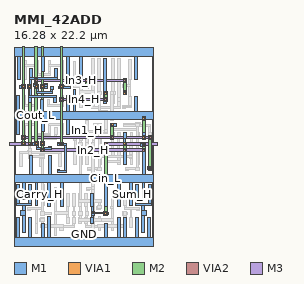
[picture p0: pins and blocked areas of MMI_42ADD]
MACRO MMI_42ADD
	CLASS CORE ;
	FOREIGN MMI_42ADD 0 0 ;
	SIZE 16.28 BY 22.2 ;
	SYMMETRY X Y ;
	SITE CORE1 ;
	PIN Sum_H
		DIRECTION output ;
		USE SIGNAL ;
		PORT
			LAYER M1 ;
			RECT 14.24 4.525 14.58 6.67 ;
			LAYER M1 ;
			RECT 15.68 4.525 16.02 6.67 ;
			LAYER M1 ;
			RECT 14.24 4.295 16.02 4.525 ;
			LAYER M1 ;
			RECT 14.91 3.64 15.25 4.295 ;
			LAYER M1 ;
			RECT 14.91 3.09 15.505 3.64 ;
			LAYER M1 ;
			RECT 14.91 1.1 15.25 3.09 ;
		END
		AntennaDiffArea 3.4977 ;
	END Sum_H
	PIN Carry_H
		DIRECTION output ;
		USE SIGNAL ;
		PORT
			LAYER M1 ;
			RECT 0.26 4.525 0.6 6.67 ;
			LAYER M1 ;
			RECT 1.7 4.525 2.04 6.67 ;
			LAYER M1 ;
			RECT 0.26 4.295 2.04 4.525 ;
			LAYER M1 ;
			RECT 1.03 3.64 1.37 4.295 ;
			LAYER M1 ;
			RECT 0.775 3.09 1.37 3.64 ;
			LAYER M1 ;
			RECT 1.03 1.1 1.37 3.09 ;
		END
		AntennaDiffArea 3.4977 ;
	END Carry_H
	PIN In2_H
		DIRECTION input ;
		USE SIGNAL ;
		PORT
			LAYER M1 ;
			RECT 3.59 18.355 3.93 18.51 ;
			LAYER M1 ;
			RECT 3.105 18.17 3.93 18.355 ;
			LAYER M1 ;
			RECT 3.105 17.905 3.92 18.17 ;
			LAYER M1 ;
			RECT 12.84 12.075 13.18 12.795 ;
			LAYER M1 ;
			RECT 3.105 11.245 3.555 11.695 ;
			LAYER M1 ;
			RECT 12.84 11.66 13.07 12.075 ;
			LAYER M1 ;
			RECT 12.76 11.28 13.14 11.66 ;
			LAYER M1 ;
			RECT 14.98 11.595 15.36 11.66 ;
			LAYER M1 ;
			RECT 14.97 11.545 15.375 11.595 ;
			LAYER M1 ;
			RECT 12.84 10.63 13.07 11.28 ;
			LAYER M1 ;
			RECT 14.81 11.205 15.375 11.545 ;
			LAYER M1 ;
			RECT 14.97 11.16 15.375 11.205 ;
			LAYER M1 ;
			RECT 12.84 9.11 13.18 10.63 ;
			LAYER VIA1 ;
			RECT 3.2 18 3.46 18.26 ;
			LAYER VIA1 ;
			RECT 3.2 11.34 3.46 11.6 ;
			LAYER VIA1 ;
			RECT 12.82 11.34 13.08 11.6 ;
			LAYER VIA1 ;
			RECT 15.04 11.34 15.3 11.6 ;
			LAYER M2 ;
			RECT 3.19 18.32 3.47 23.82 ;
			LAYER M2 ;
			RECT 3.14 17.94 3.52 18.32 ;
			LAYER M2 ;
			RECT 3.19 11.66 3.47 17.94 ;
			LAYER M2 ;
			RECT 3.14 11.28 3.52 11.66 ;
			LAYER M2 ;
			RECT 12.76 11.28 13.14 11.66 ;
			LAYER M2 ;
			RECT 14.98 11.28 15.36 11.66 ;
			LAYER M2 ;
			RECT 3.19 10.92 3.47 11.28 ;
			LAYER M2 ;
			RECT 12.81 10.92 13.09 11.28 ;
			LAYER M2 ;
			RECT 15.03 10.92 15.31 11.28 ;
			LAYER M2 ;
			RECT 3.14 10.54 3.52 10.92 ;
			LAYER M2 ;
			RECT 12.76 10.54 13.14 10.92 ;
			LAYER M2 ;
			RECT 14.98 10.54 15.36 10.92 ;
			LAYER VIA2 ;
			RECT 3.2 10.6 3.46 10.86 ;
			LAYER VIA2 ;
			RECT 12.82 10.6 13.08 10.86 ;
			LAYER VIA2 ;
			RECT 15.04 10.6 15.3 10.86 ;
			LAYER M3 ;
			RECT 3.14 10.87 3.52 10.92 ;
			LAYER M3 ;
			RECT 12.76 10.87 13.14 10.92 ;
			LAYER M3 ;
			RECT 14.98 10.87 15.36 10.92 ;
			LAYER M3 ;
			RECT 3.14 10.59 15.36 10.87 ;
			LAYER M3 ;
			RECT 3.14 10.54 3.52 10.59 ;
			LAYER M3 ;
			RECT 12.76 10.54 13.14 10.59 ;
			LAYER M3 ;
			RECT 14.98 10.54 15.36 10.59 ;
		END
		AntennaGateArea 2.7432 ;
		AntennaDiffArea 1.296 ;
	END In2_H
	PIN GND
		DIRECTION inout ;
		USE GROUND ;
		PORT
			LAYER M1 ;
			RECT 0.31 0.5 0.65 2.86 ;
			LAYER M1 ;
			RECT 1.75 0.5 2.09 2.86 ;
			LAYER M1 ;
			RECT 3.18 0.5 3.52 2.12 ;
			LAYER M1 ;
			RECT 3.96 0.5 4.3 2.925 ;
			LAYER M1 ;
			RECT 10.62 0.5 10.96 2.165 ;
			LAYER M1 ;
			RECT 12.06 0.5 12.4 2.875 ;
			LAYER M1 ;
			RECT 12.76 0.5 13.1 2.86 ;
			LAYER M1 ;
			RECT 14.19 0.5 14.53 2.86 ;
			LAYER M1 ;
			RECT 15.63 0.5 15.97 2.86 ;
			LAYER M1 ;
			RECT 0 -0.5 16.28 0.5 ;
			LAYER M1 ;
			RECT 0.26 15.3 0.6 17.13 ;
			LAYER M1 ;
			RECT 3.14 15.3 3.48 16.64 ;
			LAYER M1 ;
			RECT 6.14 15.3 6.48 17.13 ;
			LAYER M1 ;
			RECT 6.9 15.3 7.24 17.795 ;
			LAYER M1 ;
			RECT 14.08 15.3 14.42 16.965 ;
			LAYER M1 ;
			RECT 0 14.3 16.28 15.3 ;
			LAYER M1 ;
			RECT 0.3 12.555 0.64 14.3 ;
			LAYER M1 ;
			RECT 3.22 12.955 3.56 14.3 ;
			LAYER M1 ;
			RECT 6.14 12.555 6.48 14.3 ;
			LAYER M1 ;
			RECT 14.98 14.24 15.36 14.3 ;
			LAYER M1 ;
			RECT 15 12.4 15.34 12.795 ;
			LAYER M1 ;
			RECT 14.98 12.02 15.36 12.4 ;
			LAYER VIA1 ;
			RECT 15.04 14.3 15.3 14.56 ;
			LAYER VIA1 ;
			RECT 15.04 12.08 15.3 12.34 ;
			LAYER M2 ;
			RECT 14.98 14.24 15.36 14.62 ;
			LAYER M2 ;
			RECT 15.03 12.4 15.31 14.24 ;
			LAYER M2 ;
			RECT 14.98 12.02 15.36 12.4 ;
		END
	END GND
	PIN Cin_L
		DIRECTION input ;
		USE SIGNAL ;
		PORT
			LAYER M1 ;
			RECT 8.98 4.17 9.32 5.69 ;
			LAYER M1 ;
			RECT 9.09 3.52 9.32 4.17 ;
			LAYER M1 ;
			RECT 9.06 3.505 9.44 3.52 ;
			LAYER M1 ;
			RECT 10.505 3.505 10.955 3.555 ;
			LAYER M1 ;
			RECT 9.06 3.495 10.955 3.505 ;
			LAYER M1 ;
			RECT 9.06 3.275 11.09 3.495 ;
			LAYER M1 ;
			RECT 9.06 3.14 9.44 3.275 ;
			LAYER M1 ;
			RECT 10.505 3.155 11.09 3.275 ;
			LAYER M1 ;
			RECT 9.09 2.91 9.32 3.14 ;
			LAYER M1 ;
			RECT 10.505 3.105 10.955 3.155 ;
			LAYER M1 ;
			RECT 8.98 2.19 9.32 2.91 ;
			LAYER VIA1 ;
			RECT 10.6 3.2 10.86 3.46 ;
			LAYER M2 ;
			RECT 10.54 11.28 10.92 11.66 ;
			LAYER M2 ;
			RECT 10.59 3.52 10.87 11.28 ;
			LAYER M2 ;
			RECT 10.54 3.14 10.92 3.52 ;
			LAYER VIA2 ;
			RECT 10.6 11.34 10.86 11.6 ;
			LAYER M3 ;
			RECT 10.54 11.61 10.92 11.66 ;
			LAYER M3 ;
			RECT 10.54 11.33 16.79 11.61 ;
			LAYER M3 ;
			RECT 10.54 11.28 10.92 11.33 ;
		END
		AntennaGateArea 1.152 ;
		AntennaDiffArea 1.152 ;
	END Cin_L
	PIN In3_H
		DIRECTION input ;
		USE SIGNAL ;
		PORT
			LAYER M1 ;
			RECT 2.305 18.355 2.645 18.505 ;
			LAYER M1 ;
			RECT 2.305 18.165 2.815 18.355 ;
			LAYER M1 ;
			RECT 8.415 18.34 8.755 18.41 ;
			LAYER M1 ;
			RECT 2.365 17.905 2.815 18.165 ;
			LAYER M1 ;
			RECT 2.585 17.615 2.815 17.905 ;
			LAYER M1 ;
			RECT 4.32 17.795 4.66 18.135 ;
			LAYER M1 ;
			RECT 8.32 17.895 8.755 18.34 ;
			LAYER M1 ;
			RECT 4.32 17.615 4.55 17.795 ;
			LAYER M1 ;
			RECT 2.585 17.385 4.55 17.615 ;
			LAYER M1 ;
			RECT 12.76 17.2 13.14 17.755 ;
			LAYER M1 ;
			RECT 2.365 11.64 2.815 11.695 ;
			LAYER M1 ;
			RECT 2.16 11.585 2.815 11.64 ;
			LAYER M1 ;
			RECT 2.16 11.3 2.855 11.585 ;
			LAYER M1 ;
			RECT 2.365 11.245 2.855 11.3 ;
			LAYER M1 ;
			RECT 2.625 11.015 2.855 11.245 ;
			LAYER M1 ;
			RECT 4.01 11.015 4.35 11.2 ;
			LAYER M1 ;
			RECT 2.625 10.86 4.35 11.015 ;
			LAYER M1 ;
			RECT 2.625 10.785 4.245 10.86 ;
			LAYER VIA1 ;
			RECT 2.46 18 2.72 18.26 ;
			LAYER VIA1 ;
			RECT 8.38 18 8.64 18.26 ;
			LAYER VIA1 ;
			RECT 12.82 17.26 13.08 17.52 ;
			LAYER VIA1 ;
			RECT 2.46 11.34 2.72 11.6 ;
			LAYER M2 ;
			RECT 2.45 19.06 2.73 23.82 ;
			LAYER M2 ;
			RECT 2.4 18.68 2.78 19.06 ;
			LAYER M2 ;
			RECT 8.32 18.68 8.7 19.06 ;
			LAYER M2 ;
			RECT 12.76 18.68 13.14 19.06 ;
			LAYER M2 ;
			RECT 2.45 18.32 2.73 18.68 ;
			LAYER M2 ;
			RECT 8.37 18.32 8.65 18.68 ;
			LAYER M2 ;
			RECT 2.4 17.94 2.78 18.32 ;
			LAYER M2 ;
			RECT 8.32 17.94 8.7 18.32 ;
			LAYER M2 ;
			RECT 2.45 11.66 2.73 17.94 ;
			LAYER M2 ;
			RECT 12.81 17.58 13.09 18.68 ;
			LAYER M2 ;
			RECT 12.76 17.2 13.14 17.58 ;
			LAYER M2 ;
			RECT 2.4 11.28 2.78 11.66 ;
			LAYER VIA2 ;
			RECT 2.46 18.74 2.72 19 ;
			LAYER VIA2 ;
			RECT 8.38 18.74 8.64 19 ;
			LAYER VIA2 ;
			RECT 12.82 18.74 13.08 19 ;
			LAYER M3 ;
			RECT 2.4 19.01 2.78 19.06 ;
			LAYER M3 ;
			RECT 8.32 19.01 8.7 19.06 ;
			LAYER M3 ;
			RECT 12.76 19.01 13.14 19.06 ;
			LAYER M3 ;
			RECT 2.4 18.73 13.14 19.01 ;
			LAYER M3 ;
			RECT 2.4 18.68 2.78 18.73 ;
			LAYER M3 ;
			RECT 8.32 18.68 8.7 18.73 ;
			LAYER M3 ;
			RECT 12.76 18.68 13.14 18.73 ;
		END
		AntennaGateArea 4.6872 ;
	END In3_H
	PIN VDD
		DIRECTION inout ;
		USE POWER ;
		PORT
			LAYER M1 ;
			RECT 1.78 7.9 2.12 10.055 ;
			LAYER M1 ;
			RECT 4.08 7.9 4.42 10.055 ;
			LAYER M1 ;
			RECT 15 7.9 15.34 10.63 ;
			LAYER M1 ;
			RECT 0 6.9 16.28 7.9 ;
			LAYER M1 ;
			RECT 0.98 4.915 1.32 6.9 ;
			LAYER M1 ;
			RECT 2.46 4.27 2.8 6.9 ;
			LAYER M1 ;
			RECT 3.96 4.19 4.3 6.9 ;
			LAYER M1 ;
			RECT 5.4 4.19 5.74 6.9 ;
			LAYER M1 ;
			RECT 10.62 4.19 10.96 6.9 ;
			LAYER M1 ;
			RECT 12.06 4.19 12.4 6.9 ;
			LAYER M1 ;
			RECT 13.48 4.27 13.82 6.9 ;
			LAYER M1 ;
			RECT 14.96 4.915 15.3 6.9 ;
			LAYER M1 ;
			RECT 0 21.7 16.28 22.7 ;
			LAYER M1 ;
			RECT 0.38 18.97 0.72 21.7 ;
			LAYER M1 ;
			RECT 3.26 19.89 3.6 21.7 ;
			LAYER M1 ;
			RECT 6.14 18.97 6.48 21.7 ;
			LAYER M1 ;
			RECT 7.62 18.97 7.96 21.7 ;
			LAYER M1 ;
			RECT 14.08 18.97 14.42 21.7 ;
		END
	END VDD
	PIN Cout_L
		DIRECTION output ;
		USE SIGNAL ;
		PORT
			LAYER M1 ;
			RECT 1.82 19.2 2.16 20.25 ;
			LAYER M1 ;
			RECT 4.7 19.2 5.04 20.25 ;
			LAYER M1 ;
			RECT 1.82 18.97 5.04 19.2 ;
			LAYER M1 ;
			RECT 1.82 18.355 2.05 18.97 ;
			LAYER M1 ;
			RECT 1.625 17.905 2.075 18.355 ;
			LAYER M1 ;
			RECT 1.775 17.13 2.005 17.905 ;
			LAYER M1 ;
			RECT 1.7 17.1 2.04 17.13 ;
			LAYER M1 ;
			RECT 4.58 17.1 4.92 17.13 ;
			LAYER M1 ;
			RECT 1.7 16.87 4.925 17.1 ;
			LAYER M1 ;
			RECT 1.7 16.32 2.04 16.87 ;
			LAYER M1 ;
			RECT 4.58 16.32 4.92 16.87 ;
			LAYER VIA1 ;
			RECT 1.72 18 1.98 18.26 ;
			LAYER M2 ;
			RECT 1.66 17.94 2.04 18.32 ;
			LAYER M2 ;
			RECT 1.71 11.66 1.99 17.94 ;
			LAYER M2 ;
			RECT 1.66 11.28 2.04 11.66 ;
			LAYER VIA2 ;
			RECT 1.72 11.34 1.98 11.6 ;
			LAYER M3 ;
			RECT 1.66 11.61 2.04 11.66 ;
			LAYER M3 ;
			RECT -0.51 11.33 2.04 11.61 ;
			LAYER M3 ;
			RECT 1.66 11.28 2.04 11.33 ;
		END
		AntennaDiffArea 3.9528 ;
	END Cout_L
	PIN In4_H
		DIRECTION input ;
		USE SIGNAL ;
		PORT
			LAYER M1 ;
			RECT 5.325 18.355 5.57 18.36 ;
			LAYER M1 ;
			RECT 5.325 18.3 5.775 18.355 ;
			LAYER M1 ;
			RECT 5.325 18.225 6.635 18.3 ;
			LAYER M1 ;
			RECT 5.22 17.96 6.635 18.225 ;
			LAYER M1 ;
			RECT 5.22 17.905 5.775 17.96 ;
			LAYER M1 ;
			RECT 5.22 17.885 5.56 17.905 ;
			LAYER M1 ;
			RECT 5.325 17.88 5.56 17.885 ;
			LAYER M1 ;
			RECT 10.495 17.58 10.835 21.47 ;
			LAYER M1 ;
			RECT 10.495 17.2 10.92 17.58 ;
			LAYER M1 ;
			RECT 10.495 16.16 10.835 17.2 ;
			LAYER M1 ;
			RECT 5.36 11.645 5.74 11.66 ;
			LAYER M1 ;
			RECT 5.07 11.525 5.74 11.645 ;
			LAYER M1 ;
			RECT 5.07 11.51 5.775 11.525 ;
			LAYER M1 ;
			RECT 5.07 11.305 6.11 11.51 ;
			LAYER M1 ;
			RECT 5.36 11.28 6.11 11.305 ;
			LAYER M1 ;
			RECT 5.03 8.405 5.37 8.51 ;
			LAYER M1 ;
			RECT 5.88 8.405 6.11 11.28 ;
			LAYER M1 ;
			RECT 5.03 8.175 6.11 8.405 ;
			LAYER M1 ;
			RECT 5.03 8.17 5.37 8.175 ;
			LAYER VIA1 ;
			RECT 5.42 18 5.68 18.26 ;
			LAYER VIA1 ;
			RECT 10.6 17.26 10.86 17.52 ;
			LAYER VIA1 ;
			RECT 5.42 11.34 5.68 11.6 ;
			LAYER M2 ;
			RECT 5.41 18.32 5.69 23.82 ;
			LAYER M2 ;
			RECT 5.36 17.94 5.74 18.32 ;
			LAYER M2 ;
			RECT 5.41 16.84 5.69 17.94 ;
			LAYER M2 ;
			RECT 10.54 17.2 10.92 17.58 ;
			LAYER M2 ;
			RECT 10.59 16.84 10.87 17.2 ;
			LAYER M2 ;
			RECT 5.36 16.46 5.74 16.84 ;
			LAYER M2 ;
			RECT 10.54 16.46 10.92 16.84 ;
			LAYER M2 ;
			RECT 5.41 11.66 5.69 16.46 ;
			LAYER M2 ;
			RECT 5.36 11.28 5.74 11.66 ;
			LAYER VIA2 ;
			RECT 5.42 16.52 5.68 16.78 ;
			LAYER VIA2 ;
			RECT 10.6 16.52 10.86 16.78 ;
			LAYER M3 ;
			RECT 5.36 16.79 5.74 16.84 ;
			LAYER M3 ;
			RECT 10.54 16.79 10.92 16.84 ;
			LAYER M3 ;
			RECT 5.36 16.51 10.92 16.79 ;
			LAYER M3 ;
			RECT 5.36 16.46 5.74 16.51 ;
			LAYER M3 ;
			RECT 10.54 16.46 10.92 16.51 ;
		END
		AntennaGateArea 3.4992 ;
		AntennaDiffArea 3.312 ;
	END In4_H
	PIN In1_H
		DIRECTION input ;
		USE SIGNAL ;
		PORT
			LAYER M1 ;
			RECT 0.885 18.3 1.335 18.355 ;
			LAYER M1 ;
			RECT 0.7 17.96 1.335 18.3 ;
			LAYER M1 ;
			RECT 0.885 17.905 1.335 17.96 ;
			LAYER M1 ;
			RECT 11.28 13.855 11.66 13.88 ;
			LAYER M1 ;
			RECT 11.28 13.515 11.98 13.855 ;
			LAYER M1 ;
			RECT 11.28 13.5 11.66 13.515 ;
			LAYER M1 ;
			RECT 0.885 11.245 1.335 11.695 ;
			LAYER M1 ;
			RECT 15.57 8.7 15.91 8.765 ;
			LAYER M1 ;
			RECT 15.57 8.425 16.1 8.7 ;
			LAYER M1 ;
			RECT 15.72 8.32 16.1 8.425 ;
			LAYER VIA1 ;
			RECT 0.98 18 1.24 18.26 ;
			LAYER VIA1 ;
			RECT 11.34 13.56 11.6 13.82 ;
			LAYER VIA1 ;
			RECT 0.98 11.34 1.24 11.6 ;
			LAYER VIA1 ;
			RECT 15.78 8.38 16.04 8.64 ;
			LAYER M2 ;
			RECT 0.97 18.32 1.25 23.82 ;
			LAYER M2 ;
			RECT 0.92 17.94 1.3 18.32 ;
			LAYER M2 ;
			RECT 0.97 12.4 1.25 17.94 ;
			LAYER M2 ;
			RECT 11.28 13.5 11.66 13.88 ;
			LAYER M2 ;
			RECT 11.33 12.4 11.61 13.5 ;
			LAYER M2 ;
			RECT 0.92 12.02 1.3 12.4 ;
			LAYER M2 ;
			RECT 11.28 12.02 11.66 12.4 ;
			LAYER M2 ;
			RECT 15.72 12.02 16.1 12.4 ;
			LAYER M2 ;
			RECT 0.97 11.66 1.25 12.02 ;
			LAYER M2 ;
			RECT 0.92 11.28 1.3 11.66 ;
			LAYER M2 ;
			RECT 15.77 8.7 16.05 12.02 ;
			LAYER M2 ;
			RECT 15.72 8.32 16.1 8.7 ;
			LAYER VIA2 ;
			RECT 0.98 12.08 1.24 12.34 ;
			LAYER VIA2 ;
			RECT 11.34 12.08 11.6 12.34 ;
			LAYER VIA2 ;
			RECT 15.78 12.08 16.04 12.34 ;
			LAYER M3 ;
			RECT 0.92 12.35 1.3 12.4 ;
			LAYER M3 ;
			RECT 11.28 12.35 11.66 12.4 ;
			LAYER M3 ;
			RECT 15.72 12.35 16.1 12.4 ;
			LAYER M3 ;
			RECT 0.92 12.07 16.1 12.35 ;
			LAYER M3 ;
			RECT 0.92 12.02 1.3 12.07 ;
			LAYER M3 ;
			RECT 11.28 12.02 11.66 12.07 ;
			LAYER M3 ;
			RECT 15.72 12.02 16.1 12.07 ;
		END
		AntennaGateArea 3.6072 ;
	END In1_H
	OBS
		LAYER M1 ;
		RECT 1.1 20.72 1.44 21.17 ;
		LAYER M1 ;
		RECT 2.54 20.72 2.88 21.17 ;
		LAYER M1 ;
		RECT 1.1 20.49 2.88 20.72 ;
		LAYER M1 ;
		RECT 1.1 18.97 1.44 20.49 ;
		LAYER M1 ;
		RECT 2.54 19.89 2.88 20.49 ;
		LAYER M1 ;
		RECT 3.98 20.715 4.32 21.17 ;
		LAYER M1 ;
		RECT 5.42 20.715 5.76 21.17 ;
		LAYER M1 ;
		RECT 3.98 20.485 5.76 20.715 ;
		LAYER M1 ;
		RECT 3.98 19.89 4.32 20.485 ;
		LAYER M1 ;
		RECT 2.59 19.66 2.82 19.89 ;
		LAYER M1 ;
		RECT 4.03 19.66 4.26 19.89 ;
		LAYER M1 ;
		RECT 2.59 19.43 4.26 19.66 ;
		LAYER M1 ;
		RECT 5.42 18.97 5.76 20.485 ;
		LAYER M1 ;
		RECT 6.9 18.43 7.24 21.09 ;
		LAYER M1 ;
		RECT 6.9 18.035 7.96 18.43 ;
		LAYER M1 ;
		RECT 0.98 16.08 1.32 17.13 ;
		LAYER M1 ;
		RECT 2.42 16.08 2.76 16.64 ;
		LAYER M1 ;
		RECT 0.98 15.85 2.76 16.08 ;
		LAYER M1 ;
		RECT 0.98 15.83 1.32 15.85 ;
		LAYER M1 ;
		RECT 2.42 15.83 2.76 15.85 ;
		LAYER M1 ;
		RECT 3.86 16.07 4.2 16.64 ;
		LAYER M1 ;
		RECT 5.42 16.07 5.76 17.13 ;
		LAYER M1 ;
		RECT 3.86 15.84 5.76 16.07 ;
		LAYER M1 ;
		RECT 3.86 15.83 4.2 15.84 ;
		LAYER M1 ;
		RECT 5.42 15.83 5.76 15.84 ;
		LAYER M1 ;
		RECT 7.62 17.665 7.96 18.035 ;
		LAYER M1 ;
		RECT 9.055 17.665 9.395 21.47 ;
		LAYER M1 ;
		RECT 7.62 17.385 9.395 17.665 ;
		LAYER M1 ;
		RECT 7.62 15.675 7.96 17.385 ;
		LAYER M1 ;
		RECT 9.055 16.885 9.395 17.385 ;
		LAYER M1 ;
		RECT 9.05 15.89 9.395 16.885 ;
		LAYER M1 ;
		RECT 9.775 17.58 10.115 21.47 ;
		LAYER M1 ;
		RECT 11.365 17.58 11.705 21.47 ;
		LAYER M1 ;
		RECT 9.775 17.2 10.18 17.58 ;
		LAYER M1 ;
		RECT 11.28 17.2 11.81 17.58 ;
		LAYER M1 ;
		RECT 9.775 16.16 10.115 17.2 ;
		LAYER M1 ;
		RECT 11.365 16.16 11.705 17.2 ;
		LAYER M1 ;
		RECT 12.085 16.88 12.425 21.47 ;
		LAYER M1 ;
		RECT 13.36 18.97 13.7 21.29 ;
		LAYER M1 ;
		RECT 12.665 18.36 13.005 18.41 ;
		LAYER M1 ;
		RECT 13.42 18.36 13.65 18.97 ;
		LAYER M1 ;
		RECT 12.665 18.13 13.65 18.36 ;
		LAYER M1 ;
		RECT 12.665 18.07 13.005 18.13 ;
		LAYER M1 ;
		RECT 13.42 16.965 13.65 18.13 ;
		LAYER M1 ;
		RECT 12.085 16.36 12.49 16.88 ;
		LAYER M1 ;
		RECT 12.15 15.89 12.49 16.36 ;
		LAYER M1 ;
		RECT 13.36 15.95 13.7 16.965 ;
		LAYER M1 ;
		RECT 9.05 15.605 12.49 15.89 ;
		LAYER M1 ;
		RECT 12.72 15.845 13.7 15.95 ;
		LAYER M1 ;
		RECT 12.72 15.72 13.695 15.845 ;
		LAYER M1 ;
		RECT 12.72 15.61 13.06 15.72 ;
		LAYER M1 ;
		RECT 9.055 15.6 12.49 15.605 ;
		LAYER M1 ;
		RECT 9.055 15.59 12.37 15.6 ;
		LAYER M1 ;
		RECT 1.02 13.625 2.8 13.855 ;
		LAYER M1 ;
		RECT 1.02 12.555 1.36 13.625 ;
		LAYER M1 ;
		RECT 1.74 12.555 2.08 13.395 ;
		LAYER M1 ;
		RECT 2.46 12.625 2.8 13.625 ;
		LAYER M1 ;
		RECT 3.98 13.625 5.76 13.855 ;
		LAYER M1 ;
		RECT 3.98 12.625 4.32 13.625 ;
		LAYER M1 ;
		RECT 2.46 12.555 4.32 12.625 ;
		LAYER M1 ;
		RECT 4.7 12.555 5.04 13.395 ;
		LAYER M1 ;
		RECT 5.42 12.555 5.76 13.625 ;
		LAYER M1 ;
		RECT 9.675 13.795 10.18 13.88 ;
		LAYER M1 ;
		RECT 9.34 13.5 10.18 13.795 ;
		LAYER M1 ;
		RECT 14.18 13.85 14.75 13.91 ;
		LAYER M1 ;
		RECT 12.75 13.77 14.75 13.85 ;
		LAYER M1 ;
		RECT 12.75 13.54 16 13.77 ;
		LAYER M1 ;
		RECT 12.75 13.51 14.75 13.54 ;
		LAYER M1 ;
		RECT 14.18 13.5 14.75 13.51 ;
		LAYER M1 ;
		RECT 9.34 13.455 9.68 13.5 ;
		LAYER M1 ;
		RECT 10.54 13.075 10.92 13.14 ;
		LAYER M1 ;
		RECT 7.005 12.845 10.92 13.075 ;
		LAYER M1 ;
		RECT 7.005 12.615 7.235 12.845 ;
		LAYER M1 ;
		RECT 9.95 12.76 10.92 12.845 ;
		LAYER M1 ;
		RECT 11.445 13.025 14.57 13.255 ;
		LAYER M1 ;
		RECT 11.445 12.795 11.675 13.025 ;
		LAYER M1 ;
		RECT 14.34 12.795 14.57 13.025 ;
		LAYER M1 ;
		RECT 15.77 12.795 16 13.54 ;
		LAYER M1 ;
		RECT 9.95 12.695 10.875 12.76 ;
		LAYER M1 ;
		RECT 9.95 12.615 10.18 12.695 ;
		LAYER M1 ;
		RECT 1.85 12.155 2.08 12.555 ;
		LAYER M1 ;
		RECT 2.57 12.395 4.21 12.555 ;
		LAYER M1 ;
		RECT 4.7 12.155 4.93 12.555 ;
		LAYER M1 ;
		RECT 1.7 11.925 4.93 12.155 ;
		LAYER M1 ;
		RECT 1.7 10.92 1.93 11.925 ;
		LAYER M1 ;
		RECT 6.96 11.895 7.3 12.615 ;
		LAYER M1 ;
		RECT 7.68 11.895 8.02 12.615 ;
		LAYER M1 ;
		RECT 8.4 11.895 8.74 12.615 ;
		LAYER M1 ;
		RECT 9.12 11.895 9.46 12.615 ;
		LAYER M1 ;
		RECT 9.84 11.895 10.18 12.615 ;
		LAYER M1 ;
		RECT 1.66 10.72 2.04 10.92 ;
		LAYER M1 ;
		RECT 1.53 10.545 2.04 10.72 ;
		LAYER M1 ;
		RECT 0.63 10.315 5.57 10.545 ;
		LAYER M1 ;
		RECT 0.63 8.775 0.97 10.315 ;
		LAYER M1 ;
		RECT 2.93 8.775 3.27 10.315 ;
		LAYER M1 ;
		RECT 5.23 8.775 5.57 10.315 ;
		LAYER M1 ;
		RECT 7.015 10.63 7.245 11.895 ;
		LAYER M1 ;
		RECT 7.685 11.66 7.915 11.895 ;
		LAYER M1 ;
		RECT 8.4 11.66 8.63 11.895 ;
		LAYER M1 ;
		RECT 9.155 11.66 9.385 11.895 ;
		LAYER M1 ;
		RECT 7.58 11.28 7.96 11.66 ;
		LAYER M1 ;
		RECT 8.32 11.28 8.7 11.66 ;
		LAYER M1 ;
		RECT 9.06 11.28 9.44 11.66 ;
		LAYER M1 ;
		RECT 7.685 10.63 7.915 11.28 ;
		LAYER M1 ;
		RECT 8.4 10.63 8.63 11.28 ;
		LAYER M1 ;
		RECT 9.155 10.63 9.385 11.28 ;
		LAYER M1 ;
		RECT 9.95 10.63 10.18 11.895 ;
		LAYER M1 ;
		RECT 11.4 12.075 11.74 12.795 ;
		LAYER M1 ;
		RECT 12.12 12.075 12.46 12.795 ;
		LAYER M1 ;
		RECT 13.56 12.075 13.9 12.795 ;
		LAYER M1 ;
		RECT 14.28 12.075 14.62 12.795 ;
		LAYER M1 ;
		RECT 10.54 11.265 10.92 11.29 ;
		LAYER M1 ;
		RECT 10.415 10.925 10.92 11.265 ;
		LAYER M1 ;
		RECT 10.54 10.91 10.92 10.925 ;
		LAYER M1 ;
		RECT 6.96 9.11 7.3 10.63 ;
		LAYER M1 ;
		RECT 7.68 9.11 8.02 10.63 ;
		LAYER M1 ;
		RECT 8.4 9.11 8.74 10.63 ;
		LAYER M1 ;
		RECT 9.12 9.11 9.46 10.63 ;
		LAYER M1 ;
		RECT 9.84 9.11 10.18 10.63 ;
		LAYER M1 ;
		RECT 10.615 9.575 10.845 10.91 ;
		LAYER M1 ;
		RECT 11.4 10.63 11.63 12.075 ;
		LAYER M1 ;
		RECT 12.125 11.66 12.355 12.075 ;
		LAYER M1 ;
		RECT 13.595 11.66 13.825 12.075 ;
		LAYER M1 ;
		RECT 12.02 11.28 12.4 11.66 ;
		LAYER M1 ;
		RECT 13.5 11.28 13.88 11.66 ;
		LAYER M1 ;
		RECT 12.125 10.63 12.355 11.28 ;
		LAYER M1 ;
		RECT 13.595 10.63 13.825 11.28 ;
		LAYER M1 ;
		RECT 14.35 10.63 14.58 12.075 ;
		LAYER M1 ;
		RECT 15.72 12.075 16.06 12.795 ;
		LAYER M1 ;
		RECT 15.83 10.63 16.06 12.075 ;
		LAYER M1 ;
		RECT 11.4 9.82 11.74 10.63 ;
		LAYER M1 ;
		RECT 12.12 9.575 12.46 10.63 ;
		LAYER M1 ;
		RECT 10.615 9.345 12.46 9.575 ;
		LAYER M1 ;
		RECT 12.12 9.11 12.46 9.345 ;
		LAYER M1 ;
		RECT 13.56 9.11 13.9 10.63 ;
		LAYER M1 ;
		RECT 14.28 9.11 14.62 10.63 ;
		LAYER M1 ;
		RECT 8.64 8.675 8.98 8.725 ;
		LAYER M1 ;
		RECT 9.675 8.675 10.18 8.7 ;
		LAYER M1 ;
		RECT 8.64 8.445 10.18 8.675 ;
		LAYER M1 ;
		RECT 8.64 8.385 8.98 8.445 ;
		LAYER M1 ;
		RECT 9.675 8.32 10.18 8.445 ;
		LAYER M1 ;
		RECT 13.08 8.675 13.42 8.725 ;
		LAYER M1 ;
		RECT 14.24 8.675 14.62 8.7 ;
		LAYER M1 ;
		RECT 13.08 8.445 14.64 8.675 ;
		LAYER M1 ;
		RECT 13.08 8.385 13.42 8.445 ;
		LAYER M1 ;
		RECT 14.24 8.32 14.62 8.445 ;
		LAYER M1 ;
		RECT 15.72 9.11 16.06 10.63 ;
		LAYER M1 ;
		RECT 3.18 4.27 3.52 6.67 ;
		LAYER M1 ;
		RECT 1.61 4.02 1.95 4.025 ;
		LAYER M1 ;
		RECT 3.265 4.02 3.495 4.27 ;
		LAYER M1 ;
		RECT 1.61 3.79 3.495 4.02 ;
		LAYER M1 ;
		RECT 1.61 3.685 1.95 3.79 ;
		LAYER M1 ;
		RECT 2.46 2.12 2.69 3.79 ;
		LAYER M1 ;
		RECT 4.68 3.57 5.02 6.31 ;
		LAYER M1 ;
		RECT 8.46 6.405 8.8 6.415 ;
		LAYER M1 ;
		RECT 9.06 6.405 9.44 6.48 ;
		LAYER M1 ;
		RECT 8.46 6.175 9.44 6.405 ;
		LAYER M1 ;
		RECT 8.46 6.075 8.8 6.175 ;
		LAYER M1 ;
		RECT 9.06 6.1 9.44 6.175 ;
		LAYER M1 ;
		RECT 6.1 4.17 6.44 5.69 ;
		LAYER M1 ;
		RECT 6.82 4.17 7.16 5.69 ;
		LAYER M1 ;
		RECT 7.54 4.17 7.88 5.69 ;
		LAYER M1 ;
		RECT 8.26 4.17 8.6 5.69 ;
		LAYER M1 ;
		RECT 6.1 3.57 6.33 4.17 ;
		LAYER M1 ;
		RECT 3.105 3.445 3.555 3.555 ;
		LAYER M1 ;
		RECT 4.02 3.445 4.36 3.5 ;
		LAYER M1 ;
		RECT 3.105 3.215 4.36 3.445 ;
		LAYER M1 ;
		RECT 3.105 3.105 3.555 3.215 ;
		LAYER M1 ;
		RECT 4.02 3.16 4.36 3.215 ;
		LAYER M1 ;
		RECT 4.68 3.23 6.33 3.57 ;
		LAYER M1 ;
		RECT 6.895 3.52 7.125 4.17 ;
		LAYER M1 ;
		RECT 7.65 3.52 7.88 4.17 ;
		LAYER M1 ;
		RECT 8.365 3.52 8.595 4.17 ;
		LAYER M1 ;
		RECT 9.8 4.09 10.18 4.26 ;
		LAYER M1 ;
		RECT 11.34 4.185 11.68 5.71 ;
		LAYER M1 ;
		RECT 12.76 4.27 13.1 6.05 ;
		LAYER M1 ;
		RECT 9.69 3.88 10.18 4.09 ;
		LAYER M1 ;
		RECT 11.33 3.955 11.68 4.185 ;
		LAYER M1 ;
		RECT 9.69 3.75 10.16 3.88 ;
		LAYER M1 ;
		RECT 3.12 2.76 3.57 2.815 ;
		LAYER M1 ;
		RECT 2.94 2.42 3.57 2.76 ;
		LAYER M1 ;
		RECT 3.12 2.365 3.57 2.42 ;
		LAYER M1 ;
		RECT 2.46 0.96 2.8 2.12 ;
		LAYER M1 ;
		RECT 4.68 0.805 5.02 3.23 ;
		LAYER M1 ;
		RECT 6.1 2.91 6.33 3.23 ;
		LAYER M1 ;
		RECT 6.84 3.14 7.22 3.52 ;
		LAYER M1 ;
		RECT 7.58 3.14 7.96 3.52 ;
		LAYER M1 ;
		RECT 8.32 3.14 8.7 3.52 ;
		LAYER M1 ;
		RECT 6.895 2.91 7.125 3.14 ;
		LAYER M1 ;
		RECT 7.65 2.91 7.88 3.14 ;
		LAYER M1 ;
		RECT 8.365 2.91 8.595 3.14 ;
		LAYER M1 ;
		RECT 6.1 2.19 6.44 2.91 ;
		LAYER M1 ;
		RECT 6.82 2.19 7.16 2.91 ;
		LAYER M1 ;
		RECT 7.54 2.19 7.88 2.91 ;
		LAYER M1 ;
		RECT 8.26 2.19 8.6 2.91 ;
		LAYER M1 ;
		RECT 9.8 2.76 10.18 2.78 ;
		LAYER M1 ;
		RECT 11.34 2.76 11.68 3.955 ;
		LAYER M1 ;
		RECT 12.87 4.025 13.1 4.27 ;
		LAYER M1 ;
		RECT 12.87 3.795 14.67 4.025 ;
		LAYER M1 ;
		RECT 12.725 3.495 13.175 3.555 ;
		LAYER M1 ;
		RECT 12.725 3.155 13.21 3.495 ;
		LAYER M1 ;
		RECT 12.725 3.105 13.175 3.155 ;
		LAYER M1 ;
		RECT 9.8 2.42 11.68 2.76 ;
		LAYER M1 ;
		RECT 9.8 2.4 10.18 2.42 ;
		LAYER M1 ;
		RECT 6.89 1.89 7.12 2.19 ;
		LAYER M1 ;
		RECT 5.365 1.705 7.12 1.89 ;
		LAYER M1 ;
		RECT 8.365 1.955 8.595 2.19 ;
		LAYER M1 ;
		RECT 9.765 1.955 10.215 2.075 ;
		LAYER M1 ;
		RECT 8.365 1.725 10.215 1.955 ;
		LAYER M1 ;
		RECT 5.36 1.66 7.12 1.705 ;
		LAYER M1 ;
		RECT 9.8 1.66 10.18 1.725 ;
		LAYER M1 ;
		RECT 5.36 1.325 5.74 1.66 ;
		LAYER M1 ;
		RECT 7.68 1.44 8.02 1.495 ;
		LAYER M1 ;
		RECT 9.06 1.44 9.44 1.48 ;
		LAYER M1 ;
		RECT 7.68 1.21 9.44 1.44 ;
		LAYER M1 ;
		RECT 7.68 1.155 8.02 1.21 ;
		LAYER M1 ;
		RECT 9.06 1.1 9.44 1.21 ;
		LAYER M1 ;
		RECT 11.34 1.355 11.68 2.42 ;
		LAYER M1 ;
		RECT 13.555 2.86 13.785 3.795 ;
		LAYER M1 ;
		RECT 14.33 3.685 14.67 3.795 ;
		LAYER M1 ;
		RECT 13.48 1.7 13.82 2.86 ;
		LAYER VIA1 ;
		RECT 9.86 17.26 10.12 17.52 ;
		LAYER VIA1 ;
		RECT 11.34 17.26 11.6 17.52 ;
		LAYER VIA1 ;
		RECT 9.86 13.56 10.12 13.82 ;
		LAYER VIA1 ;
		RECT 14.3 13.56 14.56 13.82 ;
		LAYER VIA1 ;
		RECT 10.6 12.82 10.86 13.08 ;
		LAYER VIA1 ;
		RECT 7.64 11.34 7.9 11.6 ;
		LAYER VIA1 ;
		RECT 8.38 11.34 8.64 11.6 ;
		LAYER VIA1 ;
		RECT 9.12 11.34 9.38 11.6 ;
		LAYER VIA1 ;
		RECT 13.56 11.34 13.82 11.6 ;
		LAYER VIA1 ;
		RECT 1.72 10.6 1.98 10.86 ;
		LAYER VIA1 ;
		RECT 9.86 8.38 10.12 8.64 ;
		LAYER VIA1 ;
		RECT 14.3 8.38 14.56 8.64 ;
		LAYER VIA1 ;
		RECT 9.12 6.16 9.38 6.42 ;
		LAYER VIA1 ;
		RECT 9.86 3.94 10.12 4.2 ;
		LAYER VIA1 ;
		RECT 3.2 3.2 3.46 3.46 ;
		LAYER VIA1 ;
		RECT 7.64 3.2 7.9 3.46 ;
		LAYER VIA1 ;
		RECT 12.82 3.2 13.08 3.46 ;
		LAYER VIA1 ;
		RECT 3.2 2.46 3.46 2.72 ;
		LAYER VIA1 ;
		RECT 9.86 2.46 10.12 2.72 ;
		LAYER VIA1 ;
		RECT 9.86 1.72 10.12 1.98 ;
		LAYER VIA1 ;
		RECT 5.42 1.385 5.68 1.645 ;
		LAYER VIA1 ;
		RECT 9.12 1.16 9.38 1.42 ;
		LAYER M2 ;
		RECT 9.8 17.2 10.18 17.58 ;
		LAYER M2 ;
		RECT 11.28 17.2 11.66 17.58 ;
		LAYER M2 ;
		RECT 9.85 15.31 10.13 17.2 ;
		LAYER M2 ;
		RECT 9.85 15.03 10.87 15.31 ;
		LAYER M2 ;
		RECT 8.32 14.24 8.7 14.62 ;
		LAYER M2 ;
		RECT 8.37 11.66 8.65 14.24 ;
		LAYER M2 ;
		RECT 9.8 13.5 10.18 13.88 ;
		LAYER M2 ;
		RECT 7.58 11.28 7.96 11.66 ;
		LAYER M2 ;
		RECT 8.32 11.28 8.7 11.66 ;
		LAYER M2 ;
		RECT 9.06 11.28 9.44 11.66 ;
		LAYER M2 ;
		RECT 1.66 10.54 2.04 10.92 ;
		LAYER M2 ;
		RECT 1.71 10.18 1.99 10.54 ;
		LAYER M2 ;
		RECT 1.66 9.8 2.04 10.18 ;
		LAYER M2 ;
		RECT 3.14 9.8 3.52 10.18 ;
		LAYER M2 ;
		RECT 3.19 3.52 3.47 9.8 ;
		LAYER M2 ;
		RECT 7.63 5 7.91 11.28 ;
		LAYER M2 ;
		RECT 9.11 6.48 9.39 11.28 ;
		LAYER M2 ;
		RECT 9.85 10.18 10.13 13.5 ;
		LAYER M2 ;
		RECT 10.59 13.14 10.87 15.03 ;
		LAYER M2 ;
		RECT 11.33 14.62 11.61 17.2 ;
		LAYER M2 ;
		RECT 11.28 14.24 11.66 14.62 ;
		LAYER M2 ;
		RECT 14.24 13.5 14.62 13.88 ;
		LAYER M2 ;
		RECT 10.54 12.76 10.92 13.14 ;
		LAYER M2 ;
		RECT 13.5 11.28 13.88 11.66 ;
		LAYER M2 ;
		RECT 9.8 9.8 10.18 10.18 ;
		LAYER M2 ;
		RECT 9.85 8.7 10.13 9.8 ;
		LAYER M2 ;
		RECT 9.8 8.32 10.18 8.7 ;
		LAYER M2 ;
		RECT 9.06 6.1 9.44 6.48 ;
		LAYER M2 ;
		RECT 7.58 4.62 7.96 5 ;
		LAYER M2 ;
		RECT 3.14 3.14 3.52 3.52 ;
		LAYER M2 ;
		RECT 7.58 3.14 7.96 3.52 ;
		LAYER M2 ;
		RECT 7.63 2.78 7.91 3.14 ;
		LAYER M2 ;
		RECT 3.14 2.4 3.52 2.78 ;
		LAYER M2 ;
		RECT 7.58 2.4 7.96 2.78 ;
		LAYER M2 ;
		RECT 3.19 2.04 3.47 2.4 ;
		LAYER M2 ;
		RECT 3.14 1.66 3.52 2.04 ;
		LAYER M2 ;
		RECT 5.36 1.325 5.74 2.04 ;
		LAYER M2 ;
		RECT 9.11 1.48 9.39 6.1 ;
		LAYER M2 ;
		RECT 9.8 4.62 10.18 5 ;
		LAYER M2 ;
		RECT 9.85 4.26 10.13 4.62 ;
		LAYER M2 ;
		RECT 9.8 3.88 10.18 4.26 ;
		LAYER M2 ;
		RECT 13.55 10.18 13.83 11.28 ;
		LAYER M2 ;
		RECT 13.5 9.8 13.88 10.18 ;
		LAYER M2 ;
		RECT 14.29 8.7 14.57 13.5 ;
		LAYER M2 ;
		RECT 14.24 8.32 14.62 8.7 ;
		LAYER M2 ;
		RECT 12.76 3.14 13.14 3.52 ;
		LAYER M2 ;
		RECT 9.85 2.78 10.13 3.035 ;
		LAYER M2 ;
		RECT 9.8 2.4 10.18 2.78 ;
		LAYER M2 ;
		RECT 9.85 2.385 10.13 2.4 ;
		LAYER M2 ;
		RECT 12.81 2.04 13.09 3.14 ;
		LAYER M2 ;
		RECT 9.8 1.66 10.18 2.04 ;
		LAYER M2 ;
		RECT 12.76 1.66 13.14 2.04 ;
		LAYER M2 ;
		RECT 9.06 1.1 9.44 1.48 ;
		LAYER M2 ;
		RECT 9.85 1.34 10.13 1.66 ;
		LAYER VIA2 ;
		RECT 8.38 14.3 8.64 14.56 ;
		LAYER VIA2 ;
		RECT 11.34 14.3 11.6 14.56 ;
		LAYER VIA2 ;
		RECT 1.72 9.86 1.98 10.12 ;
		LAYER VIA2 ;
		RECT 3.2 9.86 3.46 10.12 ;
		LAYER VIA2 ;
		RECT 9.86 9.86 10.12 10.12 ;
		LAYER VIA2 ;
		RECT 13.56 9.86 13.82 10.12 ;
		LAYER VIA2 ;
		RECT 7.64 4.68 7.9 4.94 ;
		LAYER VIA2 ;
		RECT 9.86 4.68 10.12 4.94 ;
		LAYER VIA2 ;
		RECT 7.64 2.46 7.9 2.72 ;
		LAYER VIA2 ;
		RECT 9.86 2.46 10.12 2.72 ;
		LAYER VIA2 ;
		RECT 3.2 1.72 3.46 1.98 ;
		LAYER VIA2 ;
		RECT 5.42 1.72 5.68 1.98 ;
		LAYER VIA2 ;
		RECT 9.86 1.72 10.12 1.98 ;
		LAYER VIA2 ;
		RECT 12.82 1.72 13.08 1.98 ;
		LAYER M3 ;
		RECT 8.32 14.57 8.7 14.62 ;
		LAYER M3 ;
		RECT 11.28 14.57 11.66 14.62 ;
		LAYER M3 ;
		RECT 8.32 14.29 11.66 14.57 ;
		LAYER M3 ;
		RECT 8.32 14.24 8.7 14.29 ;
		LAYER M3 ;
		RECT 11.28 14.24 11.66 14.29 ;
		LAYER M3 ;
		RECT 1.66 10.13 2.04 10.18 ;
		LAYER M3 ;
		RECT 3.14 10.13 3.52 10.18 ;
		LAYER M3 ;
		RECT 1.66 9.85 3.52 10.13 ;
		LAYER M3 ;
		RECT 1.66 9.8 2.04 9.85 ;
		LAYER M3 ;
		RECT 3.14 9.8 3.52 9.85 ;
		LAYER M3 ;
		RECT 9.8 10.13 10.18 10.18 ;
		LAYER M3 ;
		RECT 13.5 10.13 13.88 10.18 ;
		LAYER M3 ;
		RECT 9.8 9.85 13.88 10.13 ;
		LAYER M3 ;
		RECT 9.8 9.8 10.18 9.85 ;
		LAYER M3 ;
		RECT 13.5 9.8 13.88 9.85 ;
		LAYER M3 ;
		RECT 7.58 4.95 7.96 5 ;
		LAYER M3 ;
		RECT 9.8 4.95 10.18 5 ;
		LAYER M3 ;
		RECT 7.58 4.67 10.18 4.95 ;
		LAYER M3 ;
		RECT 7.58 4.62 7.96 4.67 ;
		LAYER M3 ;
		RECT 9.8 4.62 10.18 4.67 ;
		LAYER M3 ;
		RECT 7.58 2.73 7.96 2.78 ;
		LAYER M3 ;
		RECT 9.8 2.73 10.18 2.78 ;
		LAYER M3 ;
		RECT 7.58 2.45 10.18 2.73 ;
		LAYER M3 ;
		RECT 7.58 2.4 7.96 2.45 ;
		LAYER M3 ;
		RECT 9.8 2.4 10.18 2.45 ;
		LAYER M3 ;
		RECT 3.14 1.99 3.52 2.04 ;
		LAYER M3 ;
		RECT 5.36 1.99 5.74 2.04 ;
		LAYER M3 ;
		RECT 3.14 1.71 5.74 1.99 ;
		LAYER M3 ;
		RECT 3.14 1.66 3.52 1.71 ;
		LAYER M3 ;
		RECT 5.36 1.66 5.74 1.71 ;
		LAYER M3 ;
		RECT 9.8 1.99 10.18 2.04 ;
		LAYER M3 ;
		RECT 12.76 1.99 13.14 2.04 ;
		LAYER M3 ;
		RECT 9.8 1.71 13.14 1.99 ;
		LAYER M3 ;
		RECT 9.8 1.66 10.18 1.71 ;
		LAYER M3 ;
		RECT 12.76 1.66 13.14 1.71 ;
	END
END MMI_42ADD
